VERSION 5.7 ;
  NOWIREEXTENSIONATPIN ON ;
  DIVIDERCHAR "/" ;
  BUSBITCHARS "[]" ;
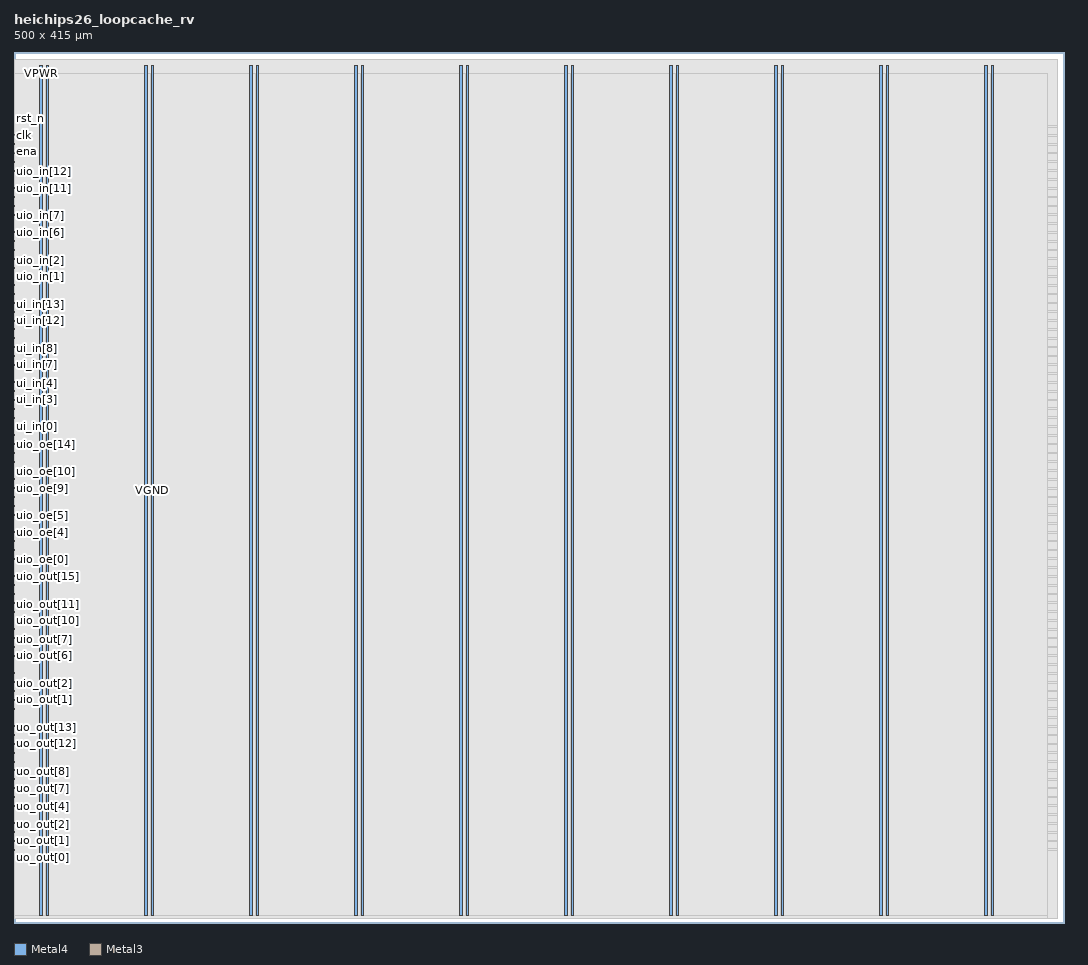
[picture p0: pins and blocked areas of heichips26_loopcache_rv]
MACRO heichips26_loopcache_rv
  CLASS BLOCK ;
  FOREIGN heichips26_loopcache_rv ;
  ORIGIN 0.000 0.000 ;
  SIZE 500.000 BY 415.000 ;
  PIN VGND
    DIRECTION INOUT ;
    USE GROUND ;
    PORT
      LAYER Metal4 ;
        RECT 15.380 3.560 16.380 408.460 ;
    END
    PORT
      LAYER Metal4 ;
        RECT 65.380 3.560 66.380 408.460 ;
    END
    PORT
      LAYER Metal4 ;
        RECT 115.380 3.560 116.380 408.460 ;
    END
    PORT
      LAYER Metal4 ;
        RECT 165.380 3.560 166.380 408.460 ;
    END
    PORT
      LAYER Metal4 ;
        RECT 215.380 3.560 216.380 408.460 ;
    END
    PORT
      LAYER Metal4 ;
        RECT 265.380 3.560 266.380 408.460 ;
    END
    PORT
      LAYER Metal4 ;
        RECT 315.380 3.560 316.380 408.460 ;
    END
    PORT
      LAYER Metal4 ;
        RECT 365.380 3.560 366.380 408.460 ;
    END
    PORT
      LAYER Metal4 ;
        RECT 415.380 3.560 416.380 408.460 ;
    END
    PORT
      LAYER Metal4 ;
        RECT 465.380 3.560 466.380 408.460 ;
    END
  END VGND
  PIN VPWR
    DIRECTION INOUT ;
    USE POWER ;
    PORT
      LAYER Metal4 ;
        RECT 12.380 3.560 13.380 408.460 ;
    END
    PORT
      LAYER Metal4 ;
        RECT 62.380 3.560 63.380 408.460 ;
    END
    PORT
      LAYER Metal4 ;
        RECT 112.380 3.560 113.380 408.460 ;
    END
    PORT
      LAYER Metal4 ;
        RECT 162.380 3.560 163.380 408.460 ;
    END
    PORT
      LAYER Metal4 ;
        RECT 212.380 3.560 213.380 408.460 ;
    END
    PORT
      LAYER Metal4 ;
        RECT 262.380 3.560 263.380 408.460 ;
    END
    PORT
      LAYER Metal4 ;
        RECT 312.380 3.560 313.380 408.460 ;
    END
    PORT
      LAYER Metal4 ;
        RECT 362.380 3.560 363.380 408.460 ;
    END
    PORT
      LAYER Metal4 ;
        RECT 412.380 3.560 413.380 408.460 ;
    END
    PORT
      LAYER Metal4 ;
        RECT 462.380 3.560 463.380 408.460 ;
    END
  END VPWR
  PIN clk
    DIRECTION INPUT ;
    USE SIGNAL ;
    ANTENNAGATEAREA 0.725400 ;
    PORT
      LAYER Metal3 ;
        RECT 0.000 374.860 0.400 375.260 ;
    END
  END clk
  PIN ena
    DIRECTION INPUT ;
    USE SIGNAL ;
    PORT
      LAYER Metal3 ;
        RECT 0.000 370.660 0.400 371.060 ;
    END
  END ena
  PIN rst_n
    DIRECTION INPUT ;
    USE SIGNAL ;
    ANTENNAGATEAREA 0.180700 ;
    PORT
      LAYER Metal3 ;
        RECT 0.000 379.060 0.400 379.460 ;
    END
  END rst_n
  PIN ui_in[0]
    DIRECTION INPUT ;
    USE SIGNAL ;
    ANTENNAGATEAREA 0.180700 ;
    PORT
      LAYER Metal3 ;
        RECT 0.000 236.260 0.400 236.660 ;
    END
  END ui_in[0]
  PIN ui_in[10]
    DIRECTION INPUT ;
    USE SIGNAL ;
    ANTENNAGATEAREA 0.180700 ;
    PORT
      LAYER Metal3 ;
        RECT 0.000 278.260 0.400 278.660 ;
    END
  END ui_in[10]
  PIN ui_in[11]
    DIRECTION INPUT ;
    USE SIGNAL ;
    ANTENNAGATEAREA 0.180700 ;
    ANTENNADIFFAREA 2.015400 ;
    PORT
      LAYER Metal3 ;
        RECT 0.000 282.460 0.400 282.860 ;
    END
  END ui_in[11]
  PIN ui_in[12]
    DIRECTION INPUT ;
    USE SIGNAL ;
    ANTENNAGATEAREA 0.180700 ;
    PORT
      LAYER Metal3 ;
        RECT 0.000 286.660 0.400 287.060 ;
    END
  END ui_in[12]
  PIN ui_in[13]
    DIRECTION INPUT ;
    USE SIGNAL ;
    ANTENNAGATEAREA 0.180700 ;
    PORT
      LAYER Metal3 ;
        RECT 0.000 290.860 0.400 291.260 ;
    END
  END ui_in[13]
  PIN ui_in[14]
    DIRECTION INPUT ;
    USE SIGNAL ;
    ANTENNAGATEAREA 0.180700 ;
    PORT
      LAYER Metal3 ;
        RECT 0.000 295.060 0.400 295.460 ;
    END
  END ui_in[14]
  PIN ui_in[15]
    DIRECTION INPUT ;
    USE SIGNAL ;
    ANTENNAGATEAREA 0.180700 ;
    PORT
      LAYER Metal3 ;
        RECT 0.000 299.260 0.400 299.660 ;
    END
  END ui_in[15]
  PIN ui_in[1]
    DIRECTION INPUT ;
    USE SIGNAL ;
    ANTENNAGATEAREA 0.180700 ;
    PORT
      LAYER Metal3 ;
        RECT 0.000 240.460 0.400 240.860 ;
    END
  END ui_in[1]
  PIN ui_in[2]
    DIRECTION INPUT ;
    USE SIGNAL ;
    ANTENNAGATEAREA 0.180700 ;
    PORT
      LAYER Metal3 ;
        RECT 0.000 244.660 0.400 245.060 ;
    END
  END ui_in[2]
  PIN ui_in[3]
    DIRECTION INPUT ;
    USE SIGNAL ;
    ANTENNAGATEAREA 0.180700 ;
    PORT
      LAYER Metal3 ;
        RECT 0.000 248.860 0.400 249.260 ;
    END
  END ui_in[3]
  PIN ui_in[4]
    DIRECTION INPUT ;
    USE SIGNAL ;
    ANTENNAGATEAREA 0.180700 ;
    PORT
      LAYER Metal3 ;
        RECT 0.000 253.060 0.400 253.460 ;
    END
  END ui_in[4]
  PIN ui_in[5]
    DIRECTION INPUT ;
    USE SIGNAL ;
    ANTENNAGATEAREA 0.180700 ;
    PORT
      LAYER Metal3 ;
        RECT 0.000 257.260 0.400 257.660 ;
    END
  END ui_in[5]
  PIN ui_in[6]
    DIRECTION INPUT ;
    USE SIGNAL ;
    ANTENNAGATEAREA 0.180700 ;
    ANTENNADIFFAREA 2.015400 ;
    PORT
      LAYER Metal3 ;
        RECT 0.000 261.460 0.400 261.860 ;
    END
  END ui_in[6]
  PIN ui_in[7]
    DIRECTION INPUT ;
    USE SIGNAL ;
    ANTENNAGATEAREA 0.180700 ;
    PORT
      LAYER Metal3 ;
        RECT 0.000 265.660 0.400 266.060 ;
    END
  END ui_in[7]
  PIN ui_in[8]
    DIRECTION INPUT ;
    USE SIGNAL ;
    ANTENNAGATEAREA 0.180700 ;
    ANTENNADIFFAREA 2.015400 ;
    PORT
      LAYER Metal3 ;
        RECT 0.000 269.860 0.400 270.260 ;
    END
  END ui_in[8]
  PIN ui_in[9]
    DIRECTION INPUT ;
    USE SIGNAL ;
    ANTENNAGATEAREA 0.180700 ;
    PORT
      LAYER Metal3 ;
        RECT 0.000 274.060 0.400 274.460 ;
    END
  END ui_in[9]
  PIN uio_in[0]
    DIRECTION INPUT ;
    USE SIGNAL ;
    ANTENNAGATEAREA 0.180700 ;
    ANTENNADIFFAREA 2.015400 ;
    PORT
      LAYER Metal3 ;
        RECT 0.000 303.460 0.400 303.860 ;
    END
  END uio_in[0]
  PIN uio_in[10]
    DIRECTION INPUT ;
    USE SIGNAL ;
    PORT
      LAYER Metal3 ;
        RECT 0.000 345.460 0.400 345.860 ;
    END
  END uio_in[10]
  PIN uio_in[11]
    DIRECTION INPUT ;
    USE SIGNAL ;
    PORT
      LAYER Metal3 ;
        RECT 0.000 349.660 0.400 350.060 ;
    END
  END uio_in[11]
  PIN uio_in[12]
    DIRECTION INPUT ;
    USE SIGNAL ;
    PORT
      LAYER Metal3 ;
        RECT 0.000 353.860 0.400 354.260 ;
    END
  END uio_in[12]
  PIN uio_in[13]
    DIRECTION INPUT ;
    USE SIGNAL ;
    PORT
      LAYER Metal3 ;
        RECT 0.000 358.060 0.400 358.460 ;
    END
  END uio_in[13]
  PIN uio_in[14]
    DIRECTION INPUT ;
    USE SIGNAL ;
    PORT
      LAYER Metal3 ;
        RECT 0.000 362.260 0.400 362.660 ;
    END
  END uio_in[14]
  PIN uio_in[15]
    DIRECTION INPUT ;
    USE SIGNAL ;
    PORT
      LAYER Metal3 ;
        RECT 0.000 366.460 0.400 366.860 ;
    END
  END uio_in[15]
  PIN uio_in[1]
    DIRECTION INPUT ;
    USE SIGNAL ;
    ANTENNAGATEAREA 0.180700 ;
    ANTENNADIFFAREA 2.015400 ;
    PORT
      LAYER Metal3 ;
        RECT 0.000 307.660 0.400 308.060 ;
    END
  END uio_in[1]
  PIN uio_in[2]
    DIRECTION INPUT ;
    USE SIGNAL ;
    ANTENNAGATEAREA 0.180700 ;
    PORT
      LAYER Metal3 ;
        RECT 0.000 311.860 0.400 312.260 ;
    END
  END uio_in[2]
  PIN uio_in[3]
    DIRECTION INPUT ;
    USE SIGNAL ;
    ANTENNAGATEAREA 0.180700 ;
    PORT
      LAYER Metal3 ;
        RECT 0.000 316.060 0.400 316.460 ;
    END
  END uio_in[3]
  PIN uio_in[4]
    DIRECTION INPUT ;
    USE SIGNAL ;
    ANTENNAGATEAREA 0.180700 ;
    PORT
      LAYER Metal3 ;
        RECT 0.000 320.260 0.400 320.660 ;
    END
  END uio_in[4]
  PIN uio_in[5]
    DIRECTION INPUT ;
    USE SIGNAL ;
    PORT
      LAYER Metal3 ;
        RECT 0.000 324.460 0.400 324.860 ;
    END
  END uio_in[5]
  PIN uio_in[6]
    DIRECTION INPUT ;
    USE SIGNAL ;
    PORT
      LAYER Metal3 ;
        RECT 0.000 328.660 0.400 329.060 ;
    END
  END uio_in[6]
  PIN uio_in[7]
    DIRECTION INPUT ;
    USE SIGNAL ;
    PORT
      LAYER Metal3 ;
        RECT 0.000 332.860 0.400 333.260 ;
    END
  END uio_in[7]
  PIN uio_in[8]
    DIRECTION INPUT ;
    USE SIGNAL ;
    PORT
      LAYER Metal3 ;
        RECT 0.000 337.060 0.400 337.460 ;
    END
  END uio_in[8]
  PIN uio_in[9]
    DIRECTION INPUT ;
    USE SIGNAL ;
    PORT
      LAYER Metal3 ;
        RECT 0.000 341.260 0.400 341.660 ;
    END
  END uio_in[9]
  PIN uio_oe[0]
    DIRECTION OUTPUT ;
    USE SIGNAL ;
    ANTENNADIFFAREA 0.392700 ;
    PORT
      LAYER Metal3 ;
        RECT 0.000 169.060 0.400 169.460 ;
    END
  END uio_oe[0]
  PIN uio_oe[10]
    DIRECTION OUTPUT ;
    USE SIGNAL ;
    ANTENNADIFFAREA 0.392700 ;
    PORT
      LAYER Metal3 ;
        RECT 0.000 211.060 0.400 211.460 ;
    END
  END uio_oe[10]
  PIN uio_oe[11]
    DIRECTION OUTPUT ;
    USE SIGNAL ;
    ANTENNADIFFAREA 0.392700 ;
    PORT
      LAYER Metal3 ;
        RECT 0.000 215.260 0.400 215.660 ;
    END
  END uio_oe[11]
  PIN uio_oe[12]
    DIRECTION OUTPUT ;
    USE SIGNAL ;
    ANTENNADIFFAREA 0.392700 ;
    PORT
      LAYER Metal3 ;
        RECT 0.000 219.460 0.400 219.860 ;
    END
  END uio_oe[12]
  PIN uio_oe[13]
    DIRECTION OUTPUT ;
    USE SIGNAL ;
    ANTENNADIFFAREA 0.392700 ;
    PORT
      LAYER Metal3 ;
        RECT 0.000 223.660 0.400 224.060 ;
    END
  END uio_oe[13]
  PIN uio_oe[14]
    DIRECTION OUTPUT ;
    USE SIGNAL ;
    ANTENNADIFFAREA 0.392700 ;
    PORT
      LAYER Metal3 ;
        RECT 0.000 227.860 0.400 228.260 ;
    END
  END uio_oe[14]
  PIN uio_oe[15]
    DIRECTION OUTPUT ;
    USE SIGNAL ;
    ANTENNADIFFAREA 0.392700 ;
    PORT
      LAYER Metal3 ;
        RECT 0.000 232.060 0.400 232.460 ;
    END
  END uio_oe[15]
  PIN uio_oe[1]
    DIRECTION OUTPUT ;
    USE SIGNAL ;
    ANTENNADIFFAREA 0.392700 ;
    PORT
      LAYER Metal3 ;
        RECT 0.000 173.260 0.400 173.660 ;
    END
  END uio_oe[1]
  PIN uio_oe[2]
    DIRECTION OUTPUT ;
    USE SIGNAL ;
    ANTENNADIFFAREA 0.392700 ;
    PORT
      LAYER Metal3 ;
        RECT 0.000 177.460 0.400 177.860 ;
    END
  END uio_oe[2]
  PIN uio_oe[3]
    DIRECTION OUTPUT ;
    USE SIGNAL ;
    ANTENNADIFFAREA 0.392700 ;
    PORT
      LAYER Metal3 ;
        RECT 0.000 181.660 0.400 182.060 ;
    END
  END uio_oe[3]
  PIN uio_oe[4]
    DIRECTION OUTPUT ;
    USE SIGNAL ;
    ANTENNADIFFAREA 0.392700 ;
    PORT
      LAYER Metal3 ;
        RECT 0.000 185.860 0.400 186.260 ;
    END
  END uio_oe[4]
  PIN uio_oe[5]
    DIRECTION OUTPUT ;
    USE SIGNAL ;
    ANTENNADIFFAREA 0.392700 ;
    PORT
      LAYER Metal3 ;
        RECT 0.000 190.060 0.400 190.460 ;
    END
  END uio_oe[5]
  PIN uio_oe[6]
    DIRECTION OUTPUT ;
    USE SIGNAL ;
    ANTENNADIFFAREA 0.392700 ;
    PORT
      LAYER Metal3 ;
        RECT 0.000 194.260 0.400 194.660 ;
    END
  END uio_oe[6]
  PIN uio_oe[7]
    DIRECTION OUTPUT ;
    USE SIGNAL ;
    ANTENNADIFFAREA 0.392700 ;
    PORT
      LAYER Metal3 ;
        RECT 0.000 198.460 0.400 198.860 ;
    END
  END uio_oe[7]
  PIN uio_oe[8]
    DIRECTION OUTPUT ;
    USE SIGNAL ;
    ANTENNADIFFAREA 0.392700 ;
    PORT
      LAYER Metal3 ;
        RECT 0.000 202.660 0.400 203.060 ;
    END
  END uio_oe[8]
  PIN uio_oe[9]
    DIRECTION OUTPUT ;
    USE SIGNAL ;
    ANTENNADIFFAREA 0.392700 ;
    PORT
      LAYER Metal3 ;
        RECT 0.000 206.860 0.400 207.260 ;
    END
  END uio_oe[9]
  PIN uio_out[0]
    DIRECTION OUTPUT ;
    USE SIGNAL ;
    ANTENNADIFFAREA 0.708600 ;
    PORT
      LAYER Metal3 ;
        RECT 0.000 101.860 0.400 102.260 ;
    END
  END uio_out[0]
  PIN uio_out[10]
    DIRECTION OUTPUT ;
    USE SIGNAL ;
    ANTENNADIFFAREA 0.708600 ;
    PORT
      LAYER Metal3 ;
        RECT 0.000 143.860 0.400 144.260 ;
    END
  END uio_out[10]
  PIN uio_out[11]
    DIRECTION OUTPUT ;
    USE SIGNAL ;
    ANTENNADIFFAREA 0.708600 ;
    PORT
      LAYER Metal3 ;
        RECT 0.000 148.060 0.400 148.460 ;
    END
  END uio_out[11]
  PIN uio_out[12]
    DIRECTION OUTPUT ;
    USE SIGNAL ;
    ANTENNADIFFAREA 0.708600 ;
    PORT
      LAYER Metal3 ;
        RECT 0.000 152.260 0.400 152.660 ;
    END
  END uio_out[12]
  PIN uio_out[13]
    DIRECTION OUTPUT ;
    USE SIGNAL ;
    ANTENNADIFFAREA 0.708600 ;
    PORT
      LAYER Metal3 ;
        RECT 0.000 156.460 0.400 156.860 ;
    END
  END uio_out[13]
  PIN uio_out[14]
    DIRECTION OUTPUT ;
    USE SIGNAL ;
    ANTENNADIFFAREA 0.708600 ;
    PORT
      LAYER Metal3 ;
        RECT 0.000 160.660 0.400 161.060 ;
    END
  END uio_out[14]
  PIN uio_out[15]
    DIRECTION OUTPUT ;
    USE SIGNAL ;
    ANTENNADIFFAREA 0.708600 ;
    PORT
      LAYER Metal3 ;
        RECT 0.000 164.860 0.400 165.260 ;
    END
  END uio_out[15]
  PIN uio_out[1]
    DIRECTION OUTPUT ;
    USE SIGNAL ;
    ANTENNADIFFAREA 0.708600 ;
    PORT
      LAYER Metal3 ;
        RECT 0.000 106.060 0.400 106.460 ;
    END
  END uio_out[1]
  PIN uio_out[2]
    DIRECTION OUTPUT ;
    USE SIGNAL ;
    ANTENNADIFFAREA 0.708600 ;
    PORT
      LAYER Metal3 ;
        RECT 0.000 110.260 0.400 110.660 ;
    END
  END uio_out[2]
  PIN uio_out[3]
    DIRECTION OUTPUT ;
    USE SIGNAL ;
    ANTENNADIFFAREA 0.708600 ;
    PORT
      LAYER Metal3 ;
        RECT 0.000 114.460 0.400 114.860 ;
    END
  END uio_out[3]
  PIN uio_out[4]
    DIRECTION OUTPUT ;
    USE SIGNAL ;
    ANTENNADIFFAREA 0.708600 ;
    PORT
      LAYER Metal3 ;
        RECT 0.000 118.660 0.400 119.060 ;
    END
  END uio_out[4]
  PIN uio_out[5]
    DIRECTION OUTPUT ;
    USE SIGNAL ;
    ANTENNADIFFAREA 0.708600 ;
    PORT
      LAYER Metal3 ;
        RECT 0.000 122.860 0.400 123.260 ;
    END
  END uio_out[5]
  PIN uio_out[6]
    DIRECTION OUTPUT ;
    USE SIGNAL ;
    ANTENNADIFFAREA 0.708600 ;
    PORT
      LAYER Metal3 ;
        RECT 0.000 127.060 0.400 127.460 ;
    END
  END uio_out[6]
  PIN uio_out[7]
    DIRECTION OUTPUT ;
    USE SIGNAL ;
    ANTENNADIFFAREA 0.708600 ;
    PORT
      LAYER Metal3 ;
        RECT 0.000 131.260 0.400 131.660 ;
    END
  END uio_out[7]
  PIN uio_out[8]
    DIRECTION OUTPUT ;
    USE SIGNAL ;
    ANTENNADIFFAREA 0.708600 ;
    PORT
      LAYER Metal3 ;
        RECT 0.000 135.460 0.400 135.860 ;
    END
  END uio_out[8]
  PIN uio_out[9]
    DIRECTION OUTPUT ;
    USE SIGNAL ;
    ANTENNADIFFAREA 0.708600 ;
    PORT
      LAYER Metal3 ;
        RECT 0.000 139.660 0.400 140.060 ;
    END
  END uio_out[9]
  PIN uo_out[0]
    DIRECTION OUTPUT ;
    USE SIGNAL ;
    ANTENNADIFFAREA 0.708600 ;
    PORT
      LAYER Metal3 ;
        RECT 0.000 34.660 0.400 35.060 ;
    END
  END uo_out[0]
  PIN uo_out[10]
    DIRECTION OUTPUT ;
    USE SIGNAL ;
    ANTENNADIFFAREA 0.708600 ;
    PORT
      LAYER Metal3 ;
        RECT 0.000 76.660 0.400 77.060 ;
    END
  END uo_out[10]
  PIN uo_out[11]
    DIRECTION OUTPUT ;
    USE SIGNAL ;
    ANTENNADIFFAREA 0.708600 ;
    PORT
      LAYER Metal3 ;
        RECT 0.000 80.860 0.400 81.260 ;
    END
  END uo_out[11]
  PIN uo_out[12]
    DIRECTION OUTPUT ;
    USE SIGNAL ;
    ANTENNADIFFAREA 0.708600 ;
    PORT
      LAYER Metal3 ;
        RECT 0.000 85.060 0.400 85.460 ;
    END
  END uo_out[12]
  PIN uo_out[13]
    DIRECTION OUTPUT ;
    USE SIGNAL ;
    ANTENNADIFFAREA 0.708600 ;
    PORT
      LAYER Metal3 ;
        RECT 0.000 89.260 0.400 89.660 ;
    END
  END uo_out[13]
  PIN uo_out[14]
    DIRECTION OUTPUT ;
    USE SIGNAL ;
    ANTENNADIFFAREA 0.708600 ;
    PORT
      LAYER Metal3 ;
        RECT 0.000 93.460 0.400 93.860 ;
    END
  END uo_out[14]
  PIN uo_out[15]
    DIRECTION OUTPUT ;
    USE SIGNAL ;
    ANTENNADIFFAREA 0.708600 ;
    PORT
      LAYER Metal3 ;
        RECT 0.000 97.660 0.400 98.060 ;
    END
  END uo_out[15]
  PIN uo_out[1]
    DIRECTION OUTPUT ;
    USE SIGNAL ;
    ANTENNADIFFAREA 0.708600 ;
    PORT
      LAYER Metal3 ;
        RECT 0.000 38.860 0.400 39.260 ;
    END
  END uo_out[1]
  PIN uo_out[2]
    DIRECTION OUTPUT ;
    USE SIGNAL ;
    ANTENNADIFFAREA 0.708600 ;
    PORT
      LAYER Metal3 ;
        RECT 0.000 43.060 0.400 43.460 ;
    END
  END uo_out[2]
  PIN uo_out[3]
    DIRECTION OUTPUT ;
    USE SIGNAL ;
    ANTENNADIFFAREA 0.708600 ;
    PORT
      LAYER Metal3 ;
        RECT 0.000 47.260 0.400 47.660 ;
    END
  END uo_out[3]
  PIN uo_out[4]
    DIRECTION OUTPUT ;
    USE SIGNAL ;
    ANTENNADIFFAREA 0.708600 ;
    PORT
      LAYER Metal3 ;
        RECT 0.000 51.460 0.400 51.860 ;
    END
  END uo_out[4]
  PIN uo_out[5]
    DIRECTION OUTPUT ;
    USE SIGNAL ;
    ANTENNADIFFAREA 0.708600 ;
    PORT
      LAYER Metal3 ;
        RECT 0.000 55.660 0.400 56.060 ;
    END
  END uo_out[5]
  PIN uo_out[6]
    DIRECTION OUTPUT ;
    USE SIGNAL ;
    ANTENNADIFFAREA 0.708600 ;
    PORT
      LAYER Metal3 ;
        RECT 0.000 59.860 0.400 60.260 ;
    END
  END uo_out[6]
  PIN uo_out[7]
    DIRECTION OUTPUT ;
    USE SIGNAL ;
    ANTENNADIFFAREA 0.708600 ;
    PORT
      LAYER Metal3 ;
        RECT 0.000 64.060 0.400 64.460 ;
    END
  END uo_out[7]
  PIN uo_out[8]
    DIRECTION OUTPUT ;
    USE SIGNAL ;
    ANTENNADIFFAREA 0.708600 ;
    PORT
      LAYER Metal3 ;
        RECT 0.000 68.260 0.400 68.660 ;
    END
  END uo_out[8]
  PIN uo_out[9]
    DIRECTION OUTPUT ;
    USE SIGNAL ;
    ANTENNADIFFAREA 0.708600 ;
    PORT
      LAYER Metal3 ;
        RECT 0.000 72.460 0.400 72.860 ;
    END
  END uo_out[9]
  OBS
      LAYER GatPoly ;
        RECT 2.880 3.630 496.800 408.390 ;
      LAYER Metal1 ;
        RECT 2.880 3.560 496.800 408.460 ;
      LAYER Metal2 ;
        RECT 0.375 1.955 496.905 411.325 ;
      LAYER Metal3 ;
        RECT 0.100 379.670 496.945 411.280 ;
        RECT 0.610 378.850 496.945 379.670 ;
        RECT 0.100 375.470 496.945 378.850 ;
        RECT 0.610 374.650 496.945 375.470 ;
        RECT 0.100 371.270 496.945 374.650 ;
        RECT 0.610 370.450 496.945 371.270 ;
        RECT 0.100 367.070 496.945 370.450 ;
        RECT 0.610 366.250 496.945 367.070 ;
        RECT 0.100 362.870 496.945 366.250 ;
        RECT 0.610 362.050 496.945 362.870 ;
        RECT 0.100 358.670 496.945 362.050 ;
        RECT 0.610 357.850 496.945 358.670 ;
        RECT 0.100 354.470 496.945 357.850 ;
        RECT 0.610 353.650 496.945 354.470 ;
        RECT 0.100 350.270 496.945 353.650 ;
        RECT 0.610 349.450 496.945 350.270 ;
        RECT 0.100 346.070 496.945 349.450 ;
        RECT 0.610 345.250 496.945 346.070 ;
        RECT 0.100 341.870 496.945 345.250 ;
        RECT 0.610 341.050 496.945 341.870 ;
        RECT 0.100 337.670 496.945 341.050 ;
        RECT 0.610 336.850 496.945 337.670 ;
        RECT 0.100 333.470 496.945 336.850 ;
        RECT 0.610 332.650 496.945 333.470 ;
        RECT 0.100 329.270 496.945 332.650 ;
        RECT 0.610 328.450 496.945 329.270 ;
        RECT 0.100 325.070 496.945 328.450 ;
        RECT 0.610 324.250 496.945 325.070 ;
        RECT 0.100 320.870 496.945 324.250 ;
        RECT 0.610 320.050 496.945 320.870 ;
        RECT 0.100 316.670 496.945 320.050 ;
        RECT 0.610 315.850 496.945 316.670 ;
        RECT 0.100 312.470 496.945 315.850 ;
        RECT 0.610 311.650 496.945 312.470 ;
        RECT 0.100 308.270 496.945 311.650 ;
        RECT 0.610 307.450 496.945 308.270 ;
        RECT 0.100 304.070 496.945 307.450 ;
        RECT 0.610 303.250 496.945 304.070 ;
        RECT 0.100 299.870 496.945 303.250 ;
        RECT 0.610 299.050 496.945 299.870 ;
        RECT 0.100 295.670 496.945 299.050 ;
        RECT 0.610 294.850 496.945 295.670 ;
        RECT 0.100 291.470 496.945 294.850 ;
        RECT 0.610 290.650 496.945 291.470 ;
        RECT 0.100 287.270 496.945 290.650 ;
        RECT 0.610 286.450 496.945 287.270 ;
        RECT 0.100 283.070 496.945 286.450 ;
        RECT 0.610 282.250 496.945 283.070 ;
        RECT 0.100 278.870 496.945 282.250 ;
        RECT 0.610 278.050 496.945 278.870 ;
        RECT 0.100 274.670 496.945 278.050 ;
        RECT 0.610 273.850 496.945 274.670 ;
        RECT 0.100 270.470 496.945 273.850 ;
        RECT 0.610 269.650 496.945 270.470 ;
        RECT 0.100 266.270 496.945 269.650 ;
        RECT 0.610 265.450 496.945 266.270 ;
        RECT 0.100 262.070 496.945 265.450 ;
        RECT 0.610 261.250 496.945 262.070 ;
        RECT 0.100 257.870 496.945 261.250 ;
        RECT 0.610 257.050 496.945 257.870 ;
        RECT 0.100 253.670 496.945 257.050 ;
        RECT 0.610 252.850 496.945 253.670 ;
        RECT 0.100 249.470 496.945 252.850 ;
        RECT 0.610 248.650 496.945 249.470 ;
        RECT 0.100 245.270 496.945 248.650 ;
        RECT 0.610 244.450 496.945 245.270 ;
        RECT 0.100 241.070 496.945 244.450 ;
        RECT 0.610 240.250 496.945 241.070 ;
        RECT 0.100 236.870 496.945 240.250 ;
        RECT 0.610 236.050 496.945 236.870 ;
        RECT 0.100 232.670 496.945 236.050 ;
        RECT 0.610 231.850 496.945 232.670 ;
        RECT 0.100 228.470 496.945 231.850 ;
        RECT 0.610 227.650 496.945 228.470 ;
        RECT 0.100 224.270 496.945 227.650 ;
        RECT 0.610 223.450 496.945 224.270 ;
        RECT 0.100 220.070 496.945 223.450 ;
        RECT 0.610 219.250 496.945 220.070 ;
        RECT 0.100 215.870 496.945 219.250 ;
        RECT 0.610 215.050 496.945 215.870 ;
        RECT 0.100 211.670 496.945 215.050 ;
        RECT 0.610 210.850 496.945 211.670 ;
        RECT 0.100 207.470 496.945 210.850 ;
        RECT 0.610 206.650 496.945 207.470 ;
        RECT 0.100 203.270 496.945 206.650 ;
        RECT 0.610 202.450 496.945 203.270 ;
        RECT 0.100 199.070 496.945 202.450 ;
        RECT 0.610 198.250 496.945 199.070 ;
        RECT 0.100 194.870 496.945 198.250 ;
        RECT 0.610 194.050 496.945 194.870 ;
        RECT 0.100 190.670 496.945 194.050 ;
        RECT 0.610 189.850 496.945 190.670 ;
        RECT 0.100 186.470 496.945 189.850 ;
        RECT 0.610 185.650 496.945 186.470 ;
        RECT 0.100 182.270 496.945 185.650 ;
        RECT 0.610 181.450 496.945 182.270 ;
        RECT 0.100 178.070 496.945 181.450 ;
        RECT 0.610 177.250 496.945 178.070 ;
        RECT 0.100 173.870 496.945 177.250 ;
        RECT 0.610 173.050 496.945 173.870 ;
        RECT 0.100 169.670 496.945 173.050 ;
        RECT 0.610 168.850 496.945 169.670 ;
        RECT 0.100 165.470 496.945 168.850 ;
        RECT 0.610 164.650 496.945 165.470 ;
        RECT 0.100 161.270 496.945 164.650 ;
        RECT 0.610 160.450 496.945 161.270 ;
        RECT 0.100 157.070 496.945 160.450 ;
        RECT 0.610 156.250 496.945 157.070 ;
        RECT 0.100 152.870 496.945 156.250 ;
        RECT 0.610 152.050 496.945 152.870 ;
        RECT 0.100 148.670 496.945 152.050 ;
        RECT 0.610 147.850 496.945 148.670 ;
        RECT 0.100 144.470 496.945 147.850 ;
        RECT 0.610 143.650 496.945 144.470 ;
        RECT 0.100 140.270 496.945 143.650 ;
        RECT 0.610 139.450 496.945 140.270 ;
        RECT 0.100 136.070 496.945 139.450 ;
        RECT 0.610 135.250 496.945 136.070 ;
        RECT 0.100 131.870 496.945 135.250 ;
        RECT 0.610 131.050 496.945 131.870 ;
        RECT 0.100 127.670 496.945 131.050 ;
        RECT 0.610 126.850 496.945 127.670 ;
        RECT 0.100 123.470 496.945 126.850 ;
        RECT 0.610 122.650 496.945 123.470 ;
        RECT 0.100 119.270 496.945 122.650 ;
        RECT 0.610 118.450 496.945 119.270 ;
        RECT 0.100 115.070 496.945 118.450 ;
        RECT 0.610 114.250 496.945 115.070 ;
        RECT 0.100 110.870 496.945 114.250 ;
        RECT 0.610 110.050 496.945 110.870 ;
        RECT 0.100 106.670 496.945 110.050 ;
        RECT 0.610 105.850 496.945 106.670 ;
        RECT 0.100 102.470 496.945 105.850 ;
        RECT 0.610 101.650 496.945 102.470 ;
        RECT 0.100 98.270 496.945 101.650 ;
        RECT 0.610 97.450 496.945 98.270 ;
        RECT 0.100 94.070 496.945 97.450 ;
        RECT 0.610 93.250 496.945 94.070 ;
        RECT 0.100 89.870 496.945 93.250 ;
        RECT 0.610 89.050 496.945 89.870 ;
        RECT 0.100 85.670 496.945 89.050 ;
        RECT 0.610 84.850 496.945 85.670 ;
        RECT 0.100 81.470 496.945 84.850 ;
        RECT 0.610 80.650 496.945 81.470 ;
        RECT 0.100 77.270 496.945 80.650 ;
        RECT 0.610 76.450 496.945 77.270 ;
        RECT 0.100 73.070 496.945 76.450 ;
        RECT 0.610 72.250 496.945 73.070 ;
        RECT 0.100 68.870 496.945 72.250 ;
        RECT 0.610 68.050 496.945 68.870 ;
        RECT 0.100 64.670 496.945 68.050 ;
        RECT 0.610 63.850 496.945 64.670 ;
        RECT 0.100 60.470 496.945 63.850 ;
        RECT 0.610 59.650 496.945 60.470 ;
        RECT 0.100 56.270 496.945 59.650 ;
        RECT 0.610 55.450 496.945 56.270 ;
        RECT 0.100 52.070 496.945 55.450 ;
        RECT 0.610 51.250 496.945 52.070 ;
        RECT 0.100 47.870 496.945 51.250 ;
        RECT 0.610 47.050 496.945 47.870 ;
        RECT 0.100 43.670 496.945 47.050 ;
        RECT 0.610 42.850 496.945 43.670 ;
        RECT 0.100 39.470 496.945 42.850 ;
        RECT 0.610 38.650 496.945 39.470 ;
        RECT 0.100 35.270 496.945 38.650 ;
        RECT 0.610 34.450 496.945 35.270 ;
        RECT 0.100 1.995 496.945 34.450 ;
      LAYER Metal4 ;
        RECT 0.380 3.350 12.170 404.605 ;
        RECT 13.590 3.350 15.170 404.605 ;
        RECT 16.590 3.350 62.170 404.605 ;
        RECT 63.590 3.350 65.170 404.605 ;
        RECT 66.590 3.350 112.170 404.605 ;
        RECT 113.590 3.350 115.170 404.605 ;
        RECT 116.590 3.350 162.170 404.605 ;
        RECT 163.590 3.350 165.170 404.605 ;
        RECT 166.590 3.350 212.170 404.605 ;
        RECT 213.590 3.350 215.170 404.605 ;
        RECT 216.590 3.350 262.170 404.605 ;
        RECT 263.590 3.350 265.170 404.605 ;
        RECT 266.590 3.350 312.170 404.605 ;
        RECT 313.590 3.350 315.170 404.605 ;
        RECT 316.590 3.350 362.170 404.605 ;
        RECT 363.590 3.350 365.170 404.605 ;
        RECT 366.590 3.350 412.170 404.605 ;
        RECT 413.590 3.350 415.170 404.605 ;
        RECT 416.590 3.350 462.170 404.605 ;
        RECT 463.590 3.350 465.170 404.605 ;
        RECT 466.590 3.350 492.100 404.605 ;
        RECT 0.380 1.955 492.100 3.350 ;
  END
END heichips26_loopcache_rv
END LIBRARY

